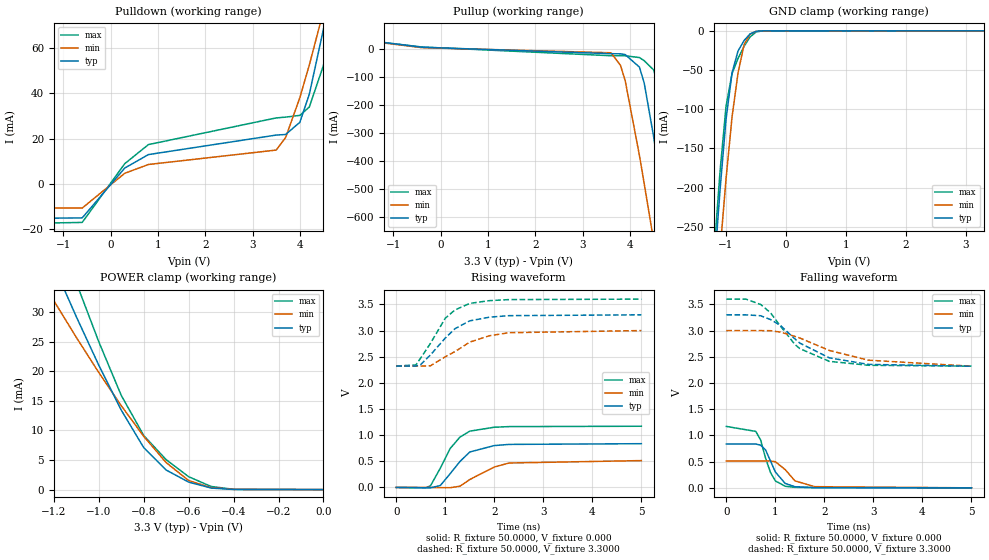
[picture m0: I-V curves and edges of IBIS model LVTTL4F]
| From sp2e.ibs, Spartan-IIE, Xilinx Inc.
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|   Model LVTTL4F
[Model]   LVTTL4F
Model_type   I/O
Polarity   Non-Inverting
Enable   Active-Low
Vinl =   0.800V
Vinh =   2.000V
Vmeas =   1.4000V
Cref =  35.0000pF
Rref =   1.0000M
Vref =  0.000V
C_comp   5.0000pF   4.0000pF   6.0000pF
[Temperature Range]   25.0000   100.0000   0.000
[Voltage Range]   3.3000V   3.0000V   3.6000V
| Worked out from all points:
|   slope of the pulldown table from 0 to 0.495 V, typ, clamps not added: 48.8 ohm
|   slope of the pullup table from 0 to 0.495 V, typ, clamps not added: 80.4 ohm
|   GND clamp passes 1 mA (typ) near -0.51 V on its own axis
|   POWER clamp passes 1 mA (typ) near -0.57 V on its own axis
|   rising waveform, R_fixture 50.0000, V_fixture 0.000: 20-80 % time 468ps typ, 630ps min, 442ps max; typ from 0 V to 0.836 V
|   rising waveform, R_fixture 50.0000, V_fixture 3.3000: 20-80 % time 635ps typ, 808ps min, 562ps max; typ from 2.32 V to 3.3 V
|   falling waveform, R_fixture 50.0000, V_fixture 0.000: 20-80 % time 272ps typ, 322ps min, 252ps max; typ from 0.836 V to 0 V
|   falling waveform, R_fixture 50.0000, V_fixture 3.3000: 20-80 % time 912ps typ, 1.26ns min, 757ps max; typ from 3.3 V to 2.32 V
[Pulldown]
| voltage   I(typ)   I(min)   I(max)
-3.3V     -15.5mA    -10.58mA   -17.86mA
-600mV    -14.92mA   -10.58mA   -16.93mA
300mV     7.091mA    4.772mA    9.036mA
800mV     13.02mA    8.645mA    17.43mA
3.5V      21.63mA    15.01mA    29.2mA
3.7V      21.89mA    20.56mA    29.55mA
4V        27.27mA    38.14mA    30.32mA
4.2V      39.63mA    52.54mA    34mA
4.5V      68.49mA    76.43mA    52.45mA
4.7V      90.09mA    93.42mA    75.12mA
4.9V      112.8mA    111.1mA    100.8mA
6.6V      325.4mA    277.2mA    349.4mA
[Pullup]
| voltage   I(typ)   I(min)   I(max)
-3.3V     66.8mA     64.5mA     64.4mA
-400mV    5.604mA    4.214mA    6.537mA
3.6V      -17.39mA   -14.17mA   -24.69mA
3.8V      -17.91mA   -59.36mA   -24.83mA
3.9V      -20.71mA   -114.4mA   -24.89mA
4.2V      -65.36mA   -380.9mA   -31.21mA
4.3V      -121.5mA   -480.7mA   -42.33mA
4.5V      -313.4mA   -685.2mA   -75.33mA
4.7V      -533.3mA   -893.2mA   -191.1mA
4.9V      -760.6mA   -1.103A    -404.8mA
5.1V      -991.3mA   -1.314A    -635.7mA
6.6V      -2.756A    -2.921A    -2.448A
[GND_clamp]
| voltage   I(typ)   I(min)   I(max)
-3.3V     -2.749A    -2.594A    -2.804A
-1.2V     -306mA     -377.1mA   -282.7mA
-1.1V     -202.5mA   -280mA     -178.8mA
-1V       -112.5mA   -188.5mA   -95.98mA
-900mV    -53.5mA    -109.7mA   -54.53mA
-800mV    -25.67mA   -53.59mA   -35.13mA
-700mV    -12.44mA   -17.88mA   -19.82mA
-600mV    -3.982mA   -4.202mA   -7.865mA
-500mV    -601.5uA   -800.3uA   -1.508mA
-400mV    -51.05uA   -119.3uA   -124.3uA
3.3V      18.74nA    3.634uA    18.92nA
[POWER_clamp]
| voltage   I(typ)   I(min)   I(max)
-3.3V     237mA      175.9mA    284.4mA
-1.3V     46.69mA    38.29mA    56.33mA
-1.2V     37.79mA    31.9mA     45.45mA
-1.1V     29.2mA     25.71mA    34.95mA
-1V       21.01mA    19.78mA    24.97mA
-900mV    13.43mA    14.17mA    15.91mA
-800mV    7.091mA    8.993mA    9.139mA
-700mV    3.305mA    4.554mA    5.052mA
-600mV    1.265mA    1.529mA    2.172mA
-500mV    263.8uA    333.6uA    531.5uA
-400mV    22.63uA    44.12uA    49.77uA
0V        18.8nA     178.8nA    22.53nA
[Ramp]
| variable   typ   min   max
dV/dt_r   0.5018/0.4922n   0.3080/0.6118n   0.7020/0.4382n
dV/dt_f   0.5880/0.9124n   0.3906/1.1524n   0.7668/0.7541n
R_load = 50.0000
[Rising Waveform]
R_fixture = 50.0000
V_fixture = 0.000
| time   V(typ)   V(min)   V(max)
0s        3.924uV    4.383uV    3.833uV
600ps     -5.916mV   152.9uV    -7.058mV
700ps     -8.077mV   -443.5uV   31.64mV
900ps     37.05mV    -4.592mV   368.9mV
1.1ns     262.5mV    -5.417mV   743.5mV
1.3ns     495.7mV    23.52mV    961.9mV
1.5ns     677.6mV    150.8mV    1.076V
2ns       800.3mV    390.4mV    1.151V
2.3ns     822.6mV    467.3mV    1.163V
5ns       836.4mV    513.3mV    1.17V
[Rising Waveform]
R_fixture = 50.0000
V_fixture = 3.3000
V_fixture_min = 3.0000
V_fixture_max = 3.6000
| time   V(typ)   V(min)   V(max)
0s        2.32V      2.32V      2.321V
400ps     2.32V      2.32V      2.342V
500ps     2.349V     2.32V      2.475V
700ps     2.535V     2.326V     2.757V
1ns       2.855V     2.498V     3.235V
1.2ns     3.036V     2.598V     3.394V
1.5ns     3.185V     2.778V     3.518V
1.9ns     3.255V     2.9V       3.571V
2.3ns     3.284V     2.958V     3.591V
5ns       3.3V       2.999V     3.6V
[Falling Waveform]
R_fixture = 50.0000
V_fixture = 0.000
| time   V(typ)   V(min)   V(max)
0s        836.4mV    513.6mV    1.172V
600ps     836.5mV    513.6mV    1.077V
700ps     814.7mV    513.7mV    912.3mV
800ps     723.7mV    514.1mV    566.1mV
900ps     513.7mV    512.7mV    294.4mV
1ns       302.6mV    498.3mV    133mV
1.2ns     84.44mV    348.8mV    30.91mV
1.4ns     21.81mV    133.5mV    10.14mV
1.8ns     4.858mV    22.85mV    3.512mV
5ns       91.91uV    164.3uV    338uV
[Falling Waveform]
R_fixture = 50.0000
V_fixture = 3.3000
V_fixture_min = 3.0000
V_fixture_max = 3.6000
| time   V(typ)   V(min)   V(max)
0s        3.3V       3V         3.6V
400ps     3.3V       3V         3.6V
700ps     3.283V     3V         3.498V
900ps     3.211V     2.998V     3.341V
1.1ns     3.1V       2.971V     3.089V
1.4ns     2.84V      2.889V     2.734V
1.5ns     2.761V     2.858V     2.656V
2.1ns     2.48V      2.621V     2.413V
2.9ns     2.355V     2.435V     2.338V
5ns       2.32V      2.32V      2.322V
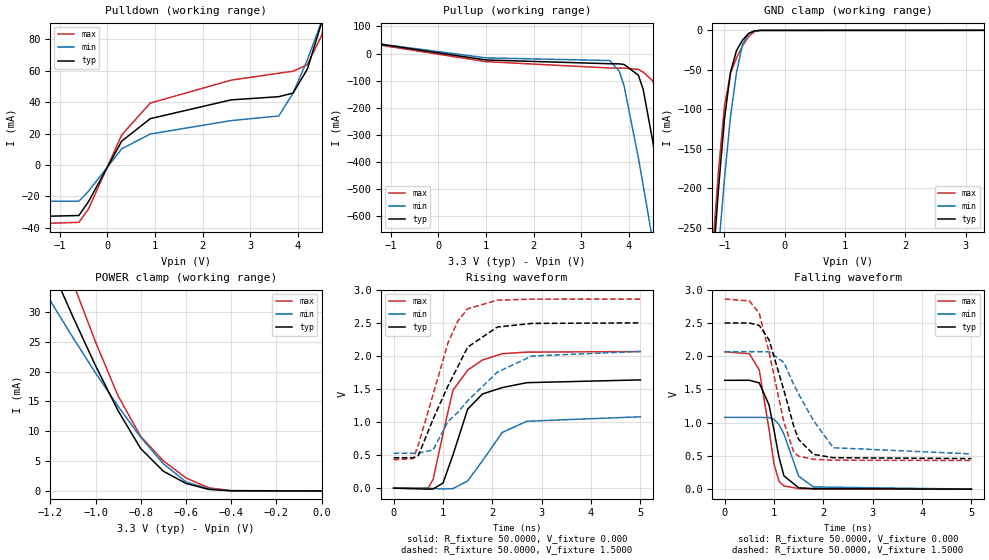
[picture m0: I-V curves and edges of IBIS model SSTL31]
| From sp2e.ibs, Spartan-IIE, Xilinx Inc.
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|   Model SSTL31
[Model]   SSTL31
Model_type   I/O
Polarity   Non-Inverting
Enable   Active-Low
Vinl =   1.300V
Vinh =   1.700V
Vmeas =   1.5000V
Cref =  30.0000pF
| The Rref below represents only the parallel load, there is actually a series
| R, see the application notes for details.
Rref =  50.0000
Vref =   1.5000V
C_comp   5.0000pF   4.0000pF   6.0000pF
[Temperature Range]   25.0000   100.0000   0.000
[Voltage Range]   3.3000V   3.0000V   3.6000V
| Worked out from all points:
|   slope of the pulldown table from 0 to 0.495 V, typ, clamps not added: 22.6 ohm
|   slope of the pullup table from 0 to 0.495 V, typ, clamps not added: 37.6 ohm
|   GND clamp passes 1 mA (typ) near -0.51 V on its own axis
|   POWER clamp passes 1 mA (typ) near -0.57 V on its own axis
|   rising waveform, R_fixture 50.0000, V_fixture 0.000: 20-80 % time 498ps typ, 630ps min, 456ps max; typ from 0 V to 1.64 V
|   rising waveform, R_fixture 50.0000, V_fixture 1.5000: 20-80 % time 758ps typ, 1.14ns min, 610ps max; typ from 0.459 V to 2.5 V
|   falling waveform, R_fixture 50.0000, V_fixture 0.000: 20-80 % time 275ps typ, 310ps min, 255ps max; typ from 1.64 V to 0 V
|   falling waveform, R_fixture 50.0000, V_fixture 1.5000: 20-80 % time 475ps typ, 645ps min, 423ps max; typ from 2.5 V to 0.46 V
[Pulldown]
| voltage   I(typ)   I(min)   I(max)
-3.3V     -33.98mA   -23.03mA   -38.9mA
-600mV    -32.1mA    -23.03mA   -36.44mA
-400mV    -23.39mA   -16.79mA   -28.09mA
300mV     15.14mA    10.3mA     19.08mA
900mV     29.43mA    19.67mA    39.34mA
2.6V      41.37mA    28.19mA    53.88mA
3.6V      43.39mA    31.15mA    58.32mA
3.9V      45.71mA    45.71mA    59.54mA
4.2V      60.95mA    66.91mA    63.71mA
4.5V      90.53mA    91.23mA    82.29mA
4.7V      112.9mA    108.6mA    105.8mA
6.6V      363.7mA    300.8mA    403.6mA
[Pullup]
| voltage   I(typ)   I(min)   I(max)
-3.3V     88.6mA     82.8mA     87.5mA
1V        -23.82mA   -16.13mA   -29.99mA
3.6V      -37.7mA    -26.01mA   -53.41mA
3.8V      -38.18mA   -66.39mA   -53.7mA
3.9V      -40.39mA   -120.1mA   -53.85mA
4.2V      -80.09mA   -385.5mA   -58.68mA
4.3V      -132.2mA   -485.2mA   -68.69mA
4.5V      -322.1mA   -689.5mA   -100.2mA
4.7V      -541.6mA   -897.5mA   -206mA
4.9V      -768.7mA   -1.107A    -417.4mA
5.1V      -999.4mA   -1.319A    -647.8mA
6.6V      -2.764A    -2.926A    -2.46A
[GND_clamp]
| voltage   I(typ)   I(min)   I(max)
-3.3V     -2.749A    -2.594A    -2.804A
-1.2V     -306mA     -377.1mA   -282.7mA
-1.1V     -202.5mA   -280mA     -178.8mA
-1V       -112.5mA   -188.5mA   -95.98mA
-900mV    -53.5mA    -109.7mA   -54.53mA
-800mV    -25.67mA   -53.59mA   -35.13mA
-700mV    -12.44mA   -17.88mA   -19.82mA
-600mV    -3.982mA   -4.202mA   -7.865mA
-500mV    -601.5uA   -800.3uA   -1.508mA
-400mV    -51.05uA   -119.3uA   -124.3uA
3.3V      18.74nA    3.634uA    18.92nA
[POWER_clamp]
| voltage   I(typ)   I(min)   I(max)
-3.3V     237mA      175.9mA    284.4mA
-1.3V     46.69mA    38.29mA    56.33mA
-1.2V     37.79mA    31.9mA     45.45mA
-1.1V     29.2mA     25.71mA    34.95mA
-1V       21.01mA    19.78mA    24.97mA
-900mV    13.43mA    14.17mA    15.91mA
-800mV    7.091mA    8.993mA    9.139mA
-700mV    3.305mA    4.554mA    5.052mA
-600mV    1.265mA    1.529mA    2.172mA
-500mV    263.8uA    333.6uA    531.5uA
-400mV    22.63uA    44.12uA    49.77uA
0V        18.8nA     38.36nA    22.53nA
[Ramp]
| variable   typ   min   max
dV/dt_r   0.9822/0.4931n   0.6474/0.6675n   1.2390/0.4639n
dV/dt_f   1.0374/0.7494n   0.7368/1.0157n   1.3338/0.6465n
R_load = 50.0000
[Rising Waveform]
R_fixture = 50.0000
V_fixture = 0.000
| time   V(typ)   V(min)   V(max)
0s        2.501uV    2.908uV    2.407uV
700ps     -15.1mV    -730.8uV   2.674mV
800ps     -12.11mV   -4.072mV   134mV
1ns       77.18mV    -12.47mV   823.2mV
1.2ns     498.1mV    -7.324mV   1.478V
1.5ns     1.194V     109.1mV    1.785V
1.8ns     1.424V     413.9mV    1.938V
2.2ns     1.52V      842.2mV    2.033V
2.7ns     1.595V     1.012V     2.057V
5ns       1.637V     1.079V     2.065V
[Rising Waveform]
R_fixture = 50.0000
V_fixture = 1.5000
V_fixture_min = 1.3000
V_fixture_max = 1.7000
| time   V(typ)   V(min)   V(max)
0s        459.1mV    528.9mV    431mV
400ps     459.2mV    529mV      447.4mV
500ps     492mV      528.9mV    656.2mV
800ps     1.045V     579.2mV    1.418V
1.1ns     1.544V     1.007V     2.194V
1.3ns     1.837V     1.145V     2.526V
1.5ns     2.131V     1.322V     2.712V
2.1ns     2.436V     1.753V     2.842V
2.8ns     2.491V     1.998V     2.858V
5ns       2.499V     2.067V     2.859V
[Falling Waveform]
R_fixture = 50.0000
V_fixture = 0.000
| time   V(typ)   V(min)   V(max)
0s        1.637V     1.08V      2.065V
500ps     1.638V     1.08V      2.037V
700ps     1.599V     1.08V      1.794V
900ps     1.264V     1.077V     893.7mV
1ns       885.4mV    1.048V     376.1mV
1.1ns     482.2mV    972.4mV    119mV
1.2ns     200.5mV    829.7mV    48.94mV
1.5ns     20.56mV    194.8mV    8.74mV
1.8ns     8.191mV    34.16mV    3.894mV
5ns       345.6uV    389.8uV    273.3uV
[Falling Waveform]
R_fixture = 50.0000
V_fixture = 1.5000
V_fixture_min = 1.3000
V_fixture_max = 1.7000
| time   V(typ)   V(min)   V(max)
0s        2.499V     2.068V     2.859V
500ps     2.499V     2.068V     2.831V
700ps     2.463V     2.068V     2.645V
900ps     2.244V     2.065V     2.058V
1.2ns     1.486V     1.905V     1.006V
1.4ns     945.2mV    1.572V     556.8mV
1.5ns     746mV      1.428V     496.3mV
1.8ns     523.6mV    1.032V     449.6mV
2.2ns     473.6mV    623mV      435.4mV
5ns       459.8mV    530.3mV    431.5mV
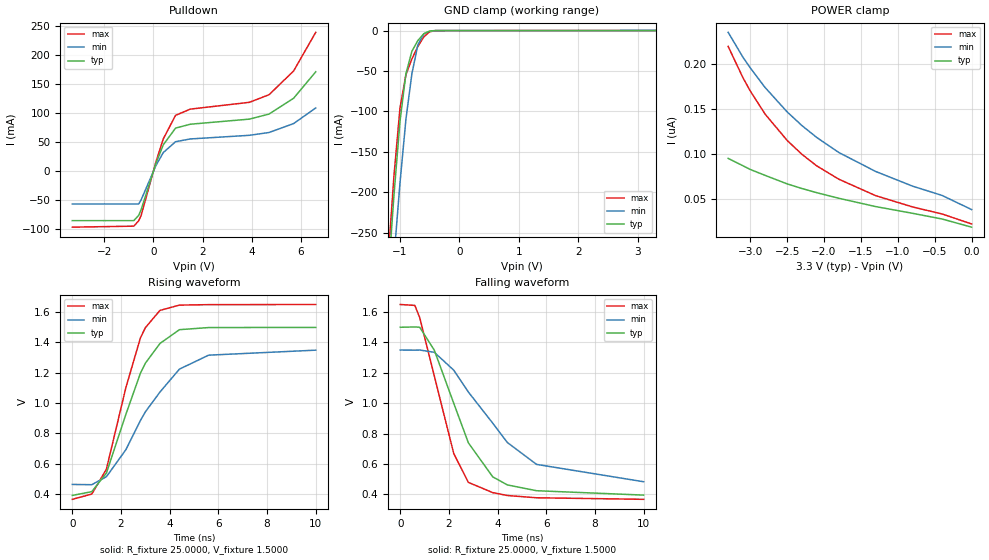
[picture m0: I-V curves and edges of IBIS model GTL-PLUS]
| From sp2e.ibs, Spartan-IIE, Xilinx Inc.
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|   Model GTL-PLUS
[Model]   GTL-PLUS
Model_type   I/O_open_drain
Polarity   Non-Inverting
Enable   Active-Low
Vinl =   0.900V
Vinh =   1.100V
Vmeas =   1.0000V
Cref =  0.000F
Rref =  25.0000
Vref =   1.5000V
C_comp   5.0000pF   4.0000pF   6.0000pF
[Temperature Range]   25.0000   100.0000   0.000
[Voltage Range]   3.3000V   3.0000V   3.6000V
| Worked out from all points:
|   slope of the pulldown table from 0 to 0.495 V, typ, clamps not added: 9.35 ohm
|   GND clamp passes 1 mA (typ) near -0.51 V on its own axis
|   rising waveform, R_fixture 25.0000, V_fixture 1.5000: 20-80 % time 1.48ns typ, 2.1ns min, 1.23ns max; typ from 0.391 V to 1.5 V
|   falling waveform, R_fixture 25.0000, V_fixture 1.5000: 20-80 % time 1.68ns typ, 2.73ns min, 1.23ns max; typ from 1.5 V to 0.394 V
[Pulldown]
| voltage   I(typ)   I(min)   I(max)
-3.3V     -85.24mA   -56.6mA    -96.47mA
-800mV    -85.23mA   -56.6mA    -94.77mA
-600mV    -76.13mA   -56.6mA    -85.45mA
-500mV    -66.19mA   -49.37mA   -76.28mA
100mV     13.08mA    9.349mA    15.65mA
400mV     45.13mA    31.78mA    55.36mA
900mV     73.81mA    50.41mA    95.78mA
1.5V      80.46mA    55.15mA    106.4mA
3.9V      89.21mA    61.37mA    118.1mA
4.7V      97.92mA    66.23mA    131.1mA
5.7V      125.1mA    81.56mA    172mA
6.6V      170.6mA    108.4mA    238.4mA
[GND_clamp]
| voltage   I(typ)   I(min)   I(max)
-3.3V     -2.749A    -2.594A    -2.804A
-1.2V     -306mA     -377.1mA   -282.7mA
-1.1V     -202.5mA   -280mA     -178.8mA
-1V       -112.5mA   -188.5mA   -95.98mA
-900mV    -53.5mA    -109.7mA   -54.53mA
-800mV    -25.67mA   -53.59mA   -35.13mA
-700mV    -12.44mA   -17.88mA   -19.82mA
-600mV    -3.982mA   -4.202mA   -7.866mA
-500mV    -601.6uA   -800.4uA   -1.508mA
-400mV    -51.05uA   -119.3uA   -124.3uA
3.3V      18.51nA    55.53nA    17.75nA
[POWER_clamp]
| voltage   I(typ)   I(min)   I(max)
-3.3V     95.11nA    235.6nA    219.9nA
-3.1V     86.96nA    207.9nA    185.1nA
-3V       82.77nA    196nA      170.2nA
-2.8V     76.25nA    174.2nA    144.6nA
-2.5V     66.71nA    146.9nA    115.1nA
-2.3V     61.58nA    131.7nA    99.65nA
-2.1V     56.93nA    118.5nA    86.85nA
-1.8V     50.7nA     101.7nA    71.94nA
-1.3V     41.44nA    80.56nA    53.61nA
-800mV    33.94nA    64.2nA     41.04nA
-400mV    27.59nA    53.84nA    33.18nA
0V        18.51nA    38.13nA    22.12nA
[Ramp]
| variable   typ   min   max
dV/dt_r   1.1886/1.7987n   0.8328/2.3475n   1.5174/1.5898n
dV/dt_f   1.1670/3.2267n   0.7680/3.9292n   1.5108/2.6818n
R_load = 25.0000
[Rising Waveform]
R_fixture = 25.0000
V_fixture = 1.5000
V_fixture_min = 1.3500
V_fixture_max = 1.6500
| time   V(typ)   V(min)   V(max)
0s        391.3mV    463.7mV    365.6mV
800ps     416.3mV    462.1mV    400.4mV
1.4ns     538.6mV    514.6mV    564.2mV
2.2ns     925.7mV    692.7mV    1.102V
2.8ns     1.198V     886.3mV    1.431V
3ns       1.263V     942mV      1.497V
3.6ns     1.393V     1.073V     1.611V
4.4ns     1.484V     1.224V     1.646V
5.6ns     1.498V     1.316V     1.649V
10ns      1.499V     1.349V     1.65V
[Falling Waveform]
R_fixture = 25.0000
V_fixture = 1.5000
V_fixture_min = 1.3500
V_fixture_max = 1.6500
| time   V(typ)   V(min)   V(max)
0s        1.5V       1.35V      1.65V
600ps     1.502V     1.349V     1.644V
800ps     1.5V       1.35V      1.564V
1.4ns     1.349V     1.335V     1.179V
2.2ns     998.2mV    1.217V     667.1mV
2.8ns     738.3mV    1.073V     477.8mV
3.8ns     514.4mV    868mV      410.5mV
4.4ns     461.3mV    740.8mV    391.5mV
5.6ns     423mV      596.5mV    376.6mV
10ns      394.1mV    482.2mV    366.3mV
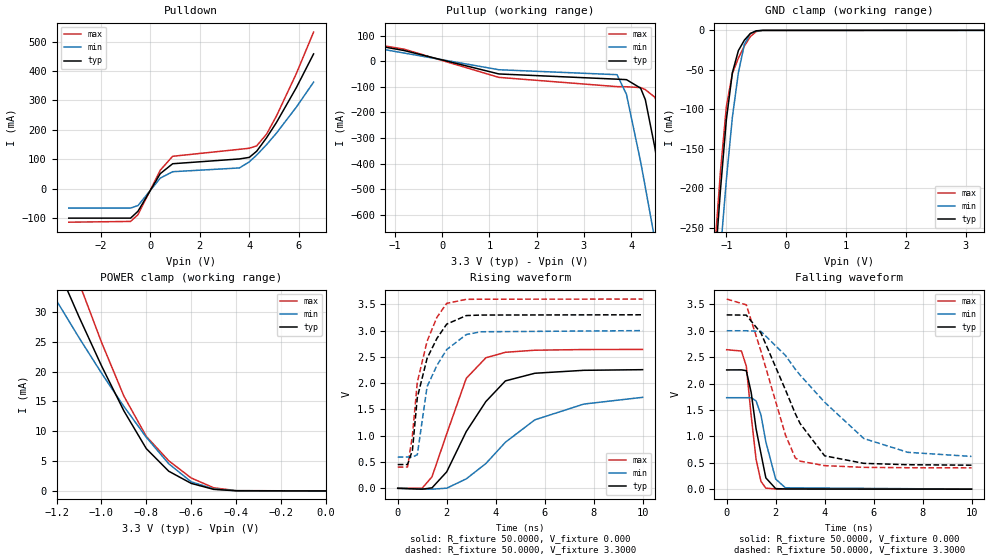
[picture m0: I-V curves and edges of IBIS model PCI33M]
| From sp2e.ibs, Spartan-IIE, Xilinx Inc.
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|   Model PCI33M
[Model]   PCI33M
Model_type   I/O
Polarity   Non-Inverting
Enable   Active-Low
Vinl =   0.900V
Vinh =   1.650V
| Vmeas depends on rising or falling edge, select one of the following:
| For rising edge:
|Vmeas =   0.940V
| For falling edge:
|Vmeas =   2.00V
Cref =  10.0000pF
Rref =  25.0000
| Vref depends on rising or falling edge, select one of the following:
| For rising edge:
|Vref =   0.00V
| For falling edge:
|Vref =   3.30V
C_comp   5.0000pF   4.0000pF   6.0000pF
[Temperature Range]   25.0000   100.0000   0.000
[Voltage Range]   3.3000V   3.0000V   3.6000V
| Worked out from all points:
|   slope of the pulldown table from 0 to 0.495 V, typ, clamps not added: 8.13 ohm
|   slope of the pullup table from 0 to 0.495 V, typ, clamps not added: 20.5 ohm
|   GND clamp passes 1 mA (typ) near -0.51 V on its own axis
|   POWER clamp passes 1 mA (typ) near -0.57 V on its own axis
|   rising waveform, R_fixture 50.0000, V_fixture 0.000: 20-80 % time 1.69ns typ, 2.85ns min, 1.17ns max; typ from 0 V to 2.26 V
|   rising waveform, R_fixture 50.0000, V_fixture 3.3000: 20-80 % time 817ps typ, 867ps min, 743ps max; typ from 0.452 V to 3.3 V
|   falling waveform, R_fixture 50.0000, V_fixture 0.000: 20-80 % time 489ps typ, 475ps min, 371ps max; typ from 2.26 V to 0 V
|   falling waveform, R_fixture 50.0000, V_fixture 3.3000: 20-80 % time 1.67ns typ, 2.84ns min, 1.24ns max; typ from 3.3 V to 0.454 V
[Pulldown]
| voltage   I(typ)   I(min)   I(max)
-3.3V     -99.23mA   -65.07mA   -113mA
-800mV    -99.23mA   -65.07mA   -110.4mA
-500mV    -75.76mA   -56.5mA    -87.37mA
400mV     51.81mA    36.52mA    63.47mA
900mV     85.36mA    58.31mA    110.6mA
3.6V      101.6mA    71.08mA    134.3mA
4V        106.9mA    91.67mA    138mA
4.3V      128mA      114.9mA    146.1mA
4.7V      173.6mA    150.3mA    186mA
5.1V      225.6mA    189.5mA    247.7mA
5.9V      343.2mA    277.2mA    390.9mA
6.6V      458.1mA    362.2mA    532.1mA
[Pullup]
| voltage   I(typ)   I(min)   I(max)
-3.3V     124mA      112.4mA    124.9mA
-800mV    41.16mA    31.48mA    46.43mA
1.2V      -50.03mA   -33.57mA   -63.45mA
3.7V      -70.41mA   -52.86mA   -99.5mA
3.9V      -72.23mA   -129.4mA   -100mA
4.2V      -105.5mA   -392.9mA   -103.2mA
4.3V      -150.5mA   -492.5mA   -111.2mA
4.5V      -336.2mA   -696.6mA   -140.6mA
4.7V      -554.8mA   -904.5mA   -231.2mA
4.9V      -781.7mA   -1.114A    -437.8mA
5.1V      -1.012A    -1.326A    -667.2mA
6.6V      -2.778A    -2.933A    -2.479A
[GND_clamp]
| voltage   I(typ)   I(min)   I(max)
-3.3V     -2.749A    -2.594A    -2.804A
-1.2V     -306mA     -377.1mA   -282.7mA
-1.1V     -202.5mA   -280mA     -178.8mA
-1V       -112.5mA   -188.5mA   -95.98mA
-900mV    -53.5mA    -109.7mA   -54.53mA
-800mV    -25.67mA   -53.59mA   -35.13mA
-700mV    -12.44mA   -17.88mA   -19.82mA
-600mV    -3.982mA   -4.202mA   -7.865mA
-500mV    -601.5uA   -800.3uA   -1.508mA
-400mV    -51.05uA   -119.3uA   -124.3uA
3.3V      18.74nA    3.634uA    18.92nA
[POWER_clamp]
| voltage   I(typ)   I(min)   I(max)
-3.3V     237mA      175.9mA    284.4mA
-1.3V     46.69mA    38.29mA    56.33mA
-1.2V     37.79mA    31.9mA     45.45mA
-1.1V     29.2mA     25.71mA    34.95mA
-1V       21.01mA    19.78mA    24.97mA
-900mV    13.43mA    14.17mA    15.91mA
-800mV    7.091mA    8.993mA    9.139mA
-700mV    3.305mA    4.554mA    5.052mA
-600mV    1.265mA    1.529mA    2.172mA
-500mV    263.8uA    333.6uA    531.5uA
-400mV    22.63uA    44.12uA    49.77uA
0V        18.8nA     38.3nA     22.53nA
[Ramp]
| variable   typ   min   max
dV/dt_r   1.3536/1.6859n   1.0182/2.7126n   1.5846/1.2120n
dV/dt_f   1.7075/1.6678n   1.4281/2.8498n   1.9177/1.1845n
R_load = 50.0000
[Rising Waveform]
R_fixture = 50.0000
V_fixture = 0.000
| time   V(typ)   V(min)   V(max)
0s        1.277uV    1.453uV    1.261uV
1ns       -16.51mV   -15.61mV   2.723mV
1.4ns     8.935mV    -16.38mV   218.8mV
2ns       312.3mV    1.97mV     1.035V
2.8ns     1.08V      179.3mV    2.092V
3.6ns     1.65V      471.1mV    2.482V
4.4ns     2.043V     876.4mV    2.587V
5.6ns     2.188V     1.302V     2.626V
7.6ns     2.244V     1.602V     2.639V
10ns      2.256V     1.73V      2.641V
[Rising Waveform]
R_fixture = 50.0000
V_fixture = 3.3000
V_fixture_min = 3.0000
V_fixture_max = 3.6000
| time   V(typ)   V(min)   V(max)
0s        452.1mV    594mV      403.5mV
400ps     452.1mV    594.1mV    405mV
600ps     721.1mV    593.7mV    1.002V
800ps     1.726V     638.9mV    2.018V
1.2ns     2.472V     1.935V     2.798V
1.6ns     2.85V      2.336V     3.251V
2ns       3.122V     2.638V     3.517V
2.8ns     3.285V     2.924V     3.594V
3.4ns     3.295V     2.977V     3.596V
10ns      3.3V       2.999V     3.599V
[Falling Waveform]
R_fixture = 50.0000
V_fixture = 0.000
| time   V(typ)   V(min)   V(max)
0s        2.258V     1.732V     2.641V
600ps     2.259V     1.732V     2.616V
800ps     2.245V     1.732V     2.334V
1ns       1.833V     1.731V     1.393V
1.2ns     1.145V     1.671V     566.3mV
1.4ns     674.2mV    1.407V     147.7mV
1.6ns     213.5mV    894.9mV    18.82mV
2ns       10.69mV    191.2mV    4.013mV
2.4ns     3.863mV    25.92mV    1.979mV
10ns      71.48uV    147.8uV    30.94uV
[Falling Waveform]
R_fixture = 50.0000
V_fixture = 3.3000
V_fixture_min = 3.0000
V_fixture_max = 3.6000
| time   V(typ)   V(min)   V(max)
0s        3.3V       3V         3.6V
800ps     3.296V     3V         3.491V
1.4ns     2.957V     2.988V     2.612V
2.4ns     1.881V     2.532V     1.026V
2.8ns     1.433V     2.274V     594.3mV
3ns       1.242V     2.16V      530mV
4ns       631.4mV    1.647V     445.6mV
5.6ns     488.8mV    959.1mV    413mV
7.4ns     463mV      697.9mV    405.9mV
10ns      454.2mV    619.9mV    403.9mV
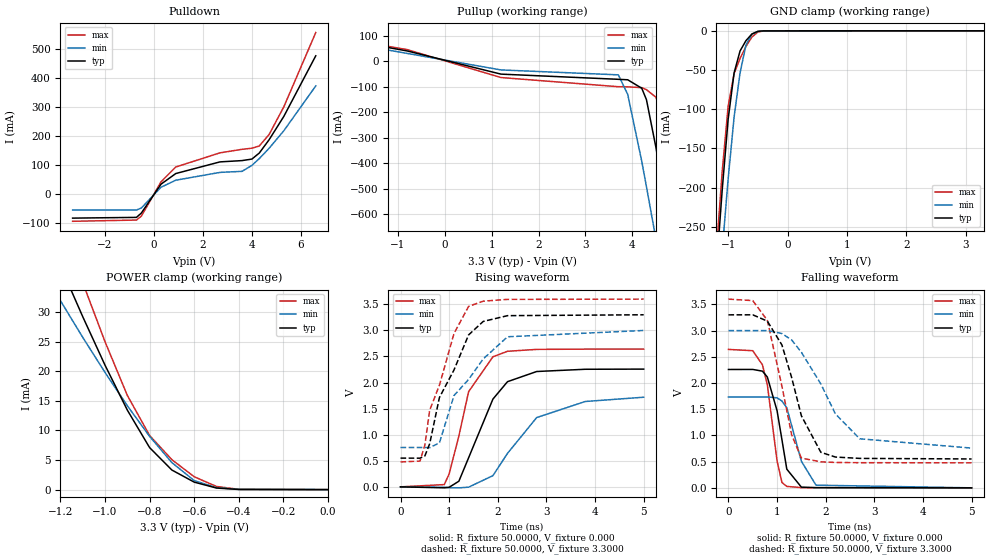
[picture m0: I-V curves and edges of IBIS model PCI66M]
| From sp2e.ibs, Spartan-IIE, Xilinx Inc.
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|   Model PCI66M
[Model]   PCI66M
Model_type   I/O
Polarity   Non-Inverting
Enable   Active-Low
Vinl =   0.900V
Vinh =   1.650V
| Vmeas depends on rising or falling edge, select one of the following:
| For rising edge:
|Vmeas =   0.940V
| For falling edge:
|Vmeas =   2.00V
Cref =  10.0000pF
Rref =  25.0000
| Vref depends on rising or falling edge, select one of the following:
| For rising edge:
|Vref =   0.00V
| For falling edge:
|Vref =   3.30V
C_comp   5.0000pF   4.0000pF   6.0000pF
[Temperature Range]   25.0000   100.0000   0.000
[Voltage Range]   3.3000V   3.0000V   3.6000V
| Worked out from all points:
|   slope of the pulldown table from 0 to 0.495 V, typ, clamps not added: 9.68 ohm
|   slope of the pullup table from 0 to 0.495 V, typ, clamps not added: 20.5 ohm
|   GND clamp passes 1 mA (typ) near -0.51 V on its own axis
|   POWER clamp passes 1 mA (typ) near -0.57 V on its own axis
|   rising waveform, R_fixture 50.0000, V_fixture 0.000: 20-80 % time 648ps typ, 890ps min, 459ps max; typ from 0 V to 2.26 V
|   rising waveform, R_fixture 50.0000, V_fixture 3.3000: 20-80 % time 664ps typ, 851ps min, 568ps max; typ from 0.551 V to 3.3 V
|   falling waveform, R_fixture 50.0000, V_fixture 0.000: 20-80 % time 260ps typ, 308ps min, 237ps max; typ from 2.26 V to 0 V
|   falling waveform, R_fixture 50.0000, V_fixture 3.3000: 20-80 % time 539ps typ, 869ps min, 403ps max; typ from 3.3 V to 0.551 V
[Pulldown]
| voltage   I(typ)   I(min)   I(max)
-3.3V     -82.43mA   -54.43mA   -93.37mA
-700mV    -79.84mA   -54.43mA   -89.08mA
-500mV    -64.76mA   -47.59mA   -75.48mA
300mV     34.67mA    24.16mA    42.73mA
900mV     71.31mA    48.33mA    93.85mA
2.7V      111.5mA    75.28mA    142.7mA
3.6V      116mA      78.93mA    154.9mA
4V        121.2mA    99.49mA    158.7mA
4.3V      142mA      122.8mA    166.3mA
4.7V      187.8mA    158.4mA    205.8mA
5.3V      268.4mA    218.9mA    301.5mA
6.6V      477.4mA    373.5mA    557.5mA
[Pullup]
| voltage   I(typ)   I(min)   I(max)
-3.3V     124mA      112.4mA    124.9mA
-800mV    41.16mA    31.48mA    46.43mA
1.2V      -50.03mA   -33.57mA   -63.45mA
3.7V      -70.41mA   -52.86mA   -99.5mA
3.9V      -72.23mA   -129.4mA   -100mA
4.2V      -105.5mA   -392.9mA   -103.2mA
4.3V      -150.5mA   -492.5mA   -111.2mA
4.5V      -336.2mA   -696.6mA   -140.6mA
4.7V      -554.8mA   -904.5mA   -231.2mA
4.9V      -781.7mA   -1.114A    -437.8mA
5.1V      -1.012A    -1.326A    -667.2mA
6.6V      -2.778A    -2.933A    -2.479A
[GND_clamp]
| voltage   I(typ)   I(min)   I(max)
-3.3V     -2.749A    -2.594A    -2.805A
-1.2V     -306mA     -377.1mA   -282.7mA
-1.1V     -202.5mA   -280mA     -178.8mA
-1V       -112.5mA   -188.5mA   -95.98mA
-900mV    -53.5mA    -109.7mA   -54.53mA
-800mV    -25.67mA   -53.59mA   -35.13mA
-700mV    -12.44mA   -17.88mA   -19.82mA
-600mV    -3.982mA   -4.202mA   -7.865mA
-500mV    -601.5uA   -800.3uA   -1.508mA
-400mV    -51.05uA   -119.3uA   -124.3uA
3.3V      18.74nA    3.634uA    18.92nA
[POWER_clamp]
| voltage   I(typ)   I(min)   I(max)
-3.3V     237mA      175.9mA    284.4mA
-1.3V     46.69mA    38.29mA    56.33mA
-1.2V     37.79mA    31.9mA     45.45mA
-1.1V     29.2mA     25.71mA    34.95mA
-1V       21.01mA    19.78mA    24.97mA
-900mV    13.43mA    14.17mA    15.91mA
-800mV    7.091mA    8.993mA    9.139mA
-700mV    3.305mA    4.554mA    5.052mA
-600mV    1.265mA    1.529mA    2.172mA
-500mV    263.8uA    333.6uA    531.5uA
-400mV    22.63uA    44.12uA    49.77uA
0V        18.8nA     38.3nA     22.53nA
[Ramp]
| variable   typ   min   max
dV/dt_r   1.3548/0.6295n   1.0314/0.9094n   1.5846/0.4697n
dV/dt_f   1.6492/0.5343n   1.3448/0.8520n   1.8732/0.3933n
R_load = 50.0000
[Rising Waveform]
R_fixture = 50.0000
V_fixture = 0.000
| time   V(typ)   V(min)   V(max)
0s        1.532uV    1.778uV    1.488uV
900ps     -18.36mV   -8.922mV   43.45mV
1ns       -7.86mV    -16.27mV   248.4mV
1.2ns     108mV      -19.3mV    976.2mV
1.4ns     557.5mV    -6.247mV   1.825V
1.9ns     1.683V     215.1mV    2.494V
2.2ns     2.017V     642mV      2.6V
2.8ns     2.212V     1.329V     2.636V
3.8ns     2.255V     1.637V     2.641V
5ns       2.258V     1.719V     2.641V
[Rising Waveform]
R_fixture = 50.0000
V_fixture = 3.3000
V_fixture_min = 3.0000
V_fixture_max = 3.6000
| time   V(typ)   V(min)   V(max)
0s        550.8mV    754.5mV    477.7mV
400ps     550.2mV    754.8mV    494.2mV
500ps     591.4mV    754.4mV    798.8mV
600ps     827.9mV    751.8mV    1.471V
800ps     1.714V     843.3mV    1.949V
1.1ns     2.243V     1.752V     2.942V
1.4ns     2.914V     2.059V     3.461V
1.7ns     3.172V     2.453V     3.561V
2.2ns     3.283V     2.878V     3.595V
5ns       3.3V       2.999V     3.6V
[Falling Waveform]
R_fixture = 50.0000
V_fixture = 0.000
| time   V(typ)   V(min)   V(max)
0s        2.258V     1.732V     2.641V
500ps     2.259V     1.732V     2.616V
700ps     2.226V     1.732V     2.345V
800ps     2.114V     1.734V     1.968V
1ns       1.472V     1.718V     513.7mV
1.1ns     919.9mV    1.656V     102.2mV
1.2ns     356.6mV    1.529V     27.83mV
1.5ns     13.61mV    507.2mV    4.693mV
1.8ns     4.733mV    51.75mV    2.204mV
5ns       181uV      335.3uV    110uV
[Falling Waveform]
R_fixture = 50.0000
V_fixture = 3.3000
V_fixture_min = 3.0000
V_fixture_max = 3.6000
| time   V(typ)   V(min)   V(max)
0s        3.3V       3V         3.6V
500ps     3.301V     3V         3.572V
800ps     3.18V      3.001V     3.195V
1.1ns     2.725V     2.943V     1.937V
1.3ns     2.104V     2.821V     1.011V
1.5ns     1.375V     2.587V     567.5mV
1.9ns     678.4mV    1.982V     496.9mV
2.2ns     587.9mV    1.41V      484.7mV
2.7ns     562.1mV    936.2mV    480mV
5ns       551.3mV    758.6mV    478mV
